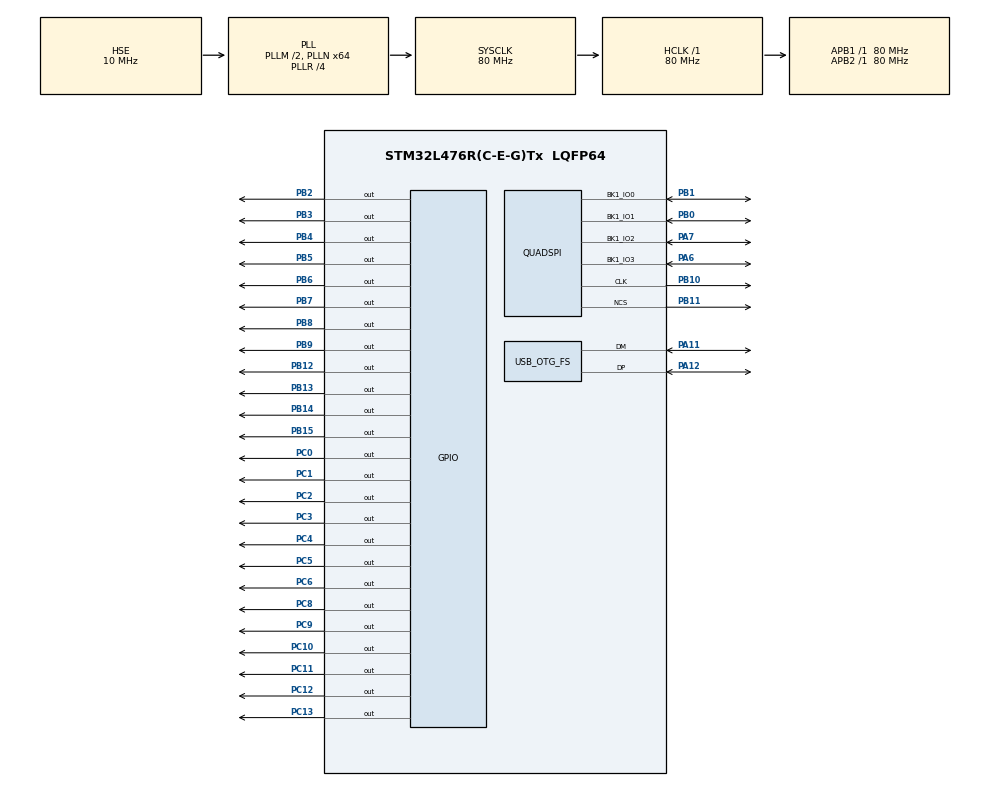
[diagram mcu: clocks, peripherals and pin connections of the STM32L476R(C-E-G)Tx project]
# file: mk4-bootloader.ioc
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CRC.InputDataFormat=CRC_INPUTDATA_FORMAT_WORDS
CRC.InputDataInversionMode=CRC_INPUTDATA_INVERSION_BYTE
CRC.OutputDataInversionMode=CRC_OUTPUTDATA_INVERSION_ENABLE
Dma.Request0=TIM1_UP
Dma.Request1=TIM4_UP
Dma.TIM1_UP.0.Direction=DMA_MEMORY_TO_PERIPH
Dma.TIM1_UP.0.Instance=DMA1_Channel6
Dma.TIM1_UP.0.MemDataAlignment=DMA_MDATAALIGN_HALFWORD
Dma.TIM1_UP.0.MemInc=DMA_MINC_ENABLE
Dma.TIM1_UP.0.Mode=DMA_CIRCULAR
Dma.TIM1_UP.0.PeriphDataAlignment=DMA_PDATAALIGN_HALFWORD
Dma.TIM1_UP.0.PeriphInc=DMA_PINC_DISABLE
Dma.TIM1_UP.0.Priority=DMA_PRIORITY_LOW
Dma.TIM4_UP.1.Direction=DMA_MEMORY_TO_PERIPH
Dma.TIM4_UP.1.Instance=DMA1_Channel7
Dma.TIM4_UP.1.MemDataAlignment=DMA_MDATAALIGN_HALFWORD
Dma.TIM4_UP.1.MemInc=DMA_MINC_ENABLE
Dma.TIM4_UP.1.Mode=DMA_CIRCULAR
Dma.TIM4_UP.1.PeriphDataAlignment=DMA_PDATAALIGN_HALFWORD
Dma.TIM4_UP.1.PeriphInc=DMA_PINC_DISABLE
Dma.TIM4_UP.1.Priority=DMA_PRIORITY_LOW
FATFS._FS_LOCK=0
FATFS._FS_READONLY=1
FATFS._MAX_SS=4096
FATFS._MIN_SS=4096
Mcu.Family=STM32L4
Mcu.Name=STM32L476R(C-E-G)Tx
Mcu.Package=LQFP64
NVIC.DMA1_Channel6_IRQn=true\:0\:0\:false\:false\:true\:false\:true
NVIC.DMA1_Channel7_IRQn=true\:0\:0\:false\:false\:true\:false\:true
NVIC.OTG_FS_IRQn=true\:0\:0\:false\:false\:true\:false\:true
NVIC.PriorityGroup=NVIC_PRIORITYGROUP_4
PA11.Mode=Device_Only
PA11.Signal=USB_OTG_FS_DM
PA12.Mode=Device_Only
PA12.Signal=USB_OTG_FS_DP
PA6.Mode=Single Bank
PA6.Signal=QUADSPI_BK1_IO3
PA7.Mode=Single Bank
PA7.Signal=QUADSPI_BK1_IO2
PB0.Mode=Single Bank
PB0.Signal=QUADSPI_BK1_IO1
PB1.Mode=Single Bank
PB1.Signal=QUADSPI_BK1_IO0
PB10.Mode=Single Bank
PB10.Signal=QUADSPI_CLK
PB11.Mode=Single Bank
PB11.Signal=QUADSPI_NCS
PB12.Signal=GPIO_Output
PB13.Signal=GPIO_Output
PB14.Signal=GPIO_Output
PB15.Signal=GPIO_Output
PB2.Signal=GPIO_Output
PB3\ (JTDO-TRACESWO).Signal=GPIO_Output
PB4\ (NJTRST).Signal=GPIO_Output
PB5.Signal=GPIO_Output
PB6.Signal=GPIO_Output
PB7.Signal=GPIO_Output
PB8.Signal=GPIO_Output
PB9.Signal=GPIO_Output
PC0.Signal=GPIO_Output
PC1.Signal=GPIO_Output
PC10.Signal=GPIO_Output
PC11.Signal=GPIO_Output
PC12.Signal=GPIO_Output
PC13.Signal=GPIO_Output
PC14-OSC32_IN\ (PC14).Mode=LSE-External-Oscillator
PC14-OSC32_IN\ (PC14).Signal=RCC_OSC32_IN
PC15-OSC32_OUT\ (PC15).Mode=LSE-External-Oscillator
PC15-OSC32_OUT\ (PC15).Signal=RCC_OSC32_OUT
PC2.Signal=GPIO_Output
PC3.Signal=GPIO_Output
PC4.Signal=GPIO_Output
PC5.Signal=GPIO_Output
PC6.Signal=GPIO_Output
PC8.Signal=GPIO_Output
PC9.Signal=GPIO_Output
PH0-OSC_IN\ (PH0).Mode=HSE-External-Oscillator
PH0-OSC_IN\ (PH0).Signal=RCC_OSC_IN
PH1-OSC_OUT\ (PH1).Mode=HSE-External-Oscillator
PH1-OSC_OUT\ (PH1).Signal=RCC_OSC_OUT
ProjectManager.HeapSize=0x200
ProjectManager.StackSize=0x400
ProjectManager.TargetToolchain=STM32CubeIDE
QUADSPI.ClockPrescaler-Single\ Bank=0
QUADSPI.FlashSize-Single\ Bank=23
QUADSPI.SampleShifting-Single\ Bank=QSPI_SAMPLE_SHIFTING_HALFCYCLE
RCC.ADCFreq_Value=20000000
RCC.AHBFreq_Value=80000000
RCC.APB1Freq_Value=80000000
RCC.APB1TimFreq_Value=80000000
RCC.APB2Freq_Value=80000000
RCC.APB2TimFreq_Value=80000000
RCC.CK48CLockSelection=RCC_USBCLKSOURCE_MSI
RCC.CortexFreq_Value=80000000
RCC.HCLKFreq_Value=80000000
RCC.HSE_VALUE=10000000
RCC.HSI_VALUE=16000000
RCC.MSIClockRange=RCC_MSIRANGE_11
RCC.MSI_VALUE=48000000
RCC.PLLM=2
RCC.PLLN=64
RCC.PLLR=RCC_PLLR_DIV4
RCC.PLLSourceVirtual=RCC_PLLSOURCE_HSE
RCC.SYSCLKFreq_VALUE=80000000
RCC.SYSCLKSource=RCC_SYSCLKSOURCE_PLLCLK
RCC.USBFreq_Value=48000000
RCC.VCOOutputFreq_Value=320000000
TIM1.Period=256
TIM4.Period=256
USB_DEVICE.CLASS_NAME_FS=MSC
USB_DEVICE.MSC_MEDIA_PACKET=4096
USB_DEVICE.VirtualMode=Msc
USB_DEVICE.VirtualModeFS=Msc_FS
USB_OTG_FS.VirtualMode=Device_Only
VP_CRC_VS_CRC.Mode=CRC_Activate
VP_FATFS_VS_Generic.Mode=User_defined
VP_TIM1_VS_ClockSourceINT.Mode=Internal
VP_TIM4_VS_ClockSourceINT.Mode=Internal
VP_USB_DEVICE_VS_USB_DEVICE_MSC_FS.Mode=MSC_FS
board=custom

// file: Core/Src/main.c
/* USER CODE BEGIN Header */
/**
  ******************************************************************************
  * @file           : main.c
  * @brief          : Main program body
  ******************************************************************************
  * @attention
  *
  * <h2><center>&copy; Copyright (c) 2021 STMicroelectronics.
  * All rights reserved.</center></h2>
  *
  * This software component is licensed by ST under BSD 3-Clause license,
  * the "License"; You may not use this file except in compliance with the
  * License. You may obtain a copy of the License at:
  *                        opensource.org/licenses/BSD-3-Clause
  *
  ******************************************************************************
  */
/* USER CODE END Header */

#include "main.h"
#include "fatfs.h"
#include "usb_device.h"

/* USER CODE BEGIN Includes */
#include "qspi_drv.h"
/* USER CODE END Includes */

CRC_HandleTypeDef hcrc;

QSPI_HandleTypeDef hqspi;

TIM_HandleTypeDef htim1;
TIM_HandleTypeDef htim4;
DMA_HandleTypeDef hdma_tim1_up;
DMA_HandleTypeDef hdma_tim4_up;

void SystemClock_Config(void);
static void MX_GPIO_Init(void);
static void MX_DMA_Init(void);
static void MX_CRC_Init(void);
static void MX_QUADSPI_Init(void);
static void MX_TIM1_Init(void);
static void MX_TIM4_Init(void);

/* USER CODE BEGIN 0 */

#define byteswap32(x) \
   ( ((x & 0xff000000) >> 24) | ((x & 0x00ff0000) >> 8) \
   | ((x & 0x0000ff00) <<  8) | ((x & 0x000000ff) << 24))

struct {
  uint8_t low;
  uint8_t high;
} buffer_c[80] = {0};

uint16_t buffer_b[80] = {0};
uint8_t animationPeriod = 2;

char animationFrame=99;
#define startAnimation() animationFrame=0
#define stopAnimation() animationFrame=99

// This method of passing variables from the linker script assumes everything is an address.
// boot size is obviously not an address, but this still works, so whatever.
extern uint32_t _boot_size[];
extern uint32_t _app_start[];
extern uint32_t _app_size[];

#define BOOT_SIZE (int)_boot_size
#define APP_SIZE (int)_app_size

void setDisplayPWM(uint32_t bright){
  HAL_DMA_Abort(&hdma_tim1_up);
  HAL_DMA_Abort(&hdma_tim4_up);
  HAL_DMA_Start(&hdma_tim1_up, (uint32_t)buffer_b, (uint32_t)&GPIOB->ODR, bright);
  HAL_DMA_Start(&hdma_tim4_up, (uint32_t)buffer_c, (uint32_t)&GPIOC->ODR, bright);
}

volatile uint8_t ejected_state = 0;

void hang_error(uint16_t errno){
  MX_USB_DEVICE_Init();

  stopAnimation();
  setDisplayPWM(5);

  buffer_b[0] = bCat0 | 0b0111110000; //b
  buffer_b[1] = bCat1 | errno;

  buffer_b[4] = bCat4 | 0b0111100100; //E
  buffer_c[0].low=0b01010000; //r
  buffer_c[1].low=0b01010000; //r
  buffer_c[2].low=0b01011100; //o
  buffer_c[3].low=0b01010000; //r

  HAL_FLASH_Lock();
  while(1){
    if (ejected_state>1) NVIC_SystemReset();
  }
}

// Get the CRC of the firmware file on FATFS
// If the CRC is wrong, immediately throw an error.
// The firmware file is padded to a fixed length, we don't need to worry about lengths not divisible by 4.
uint32_t f_crc(FIL* fp)
{
#define READ_BLOCK_SIZE (4096*2)
  unsigned int rc;
  char buf[READ_BLOCK_SIZE];
  uint32_t result;

  if ((fp)->fptr !=0) // pointless but just in case
    f_rewind(fp);

  if ((fp)->obj.objsize != APP_SIZE)
    hang_error(ERR_FS_IMG_CRC_INVALID);

  hcrc.State = HAL_CRC_STATE_BUSY;
  __HAL_CRC_DR_RESET(&hcrc);

  while ((fp)->fptr < APP_SIZE -READ_BLOCK_SIZE && !fp->err) {
    f_read(fp, &buf, READ_BLOCK_SIZE, &rc);
    for (int j=0; j<READ_BLOCK_SIZE; j+=4)
      hcrc.Instance->DR = buf[j+3] | (buf[j+2]<<8) | (buf[j+1]<<16) | (buf[j]<<24);
  }
  f_read(fp, &buf, READ_BLOCK_SIZE-4, &rc);
  for (int j=0; j<READ_BLOCK_SIZE-4; j+=4)
    hcrc.Instance->DR = buf[j+3] | (buf[j+2]<<8) | (buf[j+1]<<16) | (buf[j]<<24);

  result = ~(hcrc.Instance->DR);
  hcrc.State = HAL_CRC_STATE_READY;

  f_read(fp, &buf, 4, &rc);
  if (fp->err || result != (buf[3] | (buf[2]<<8) | (buf[1]<<16) | (buf[0]<<24)) )
    hang_error(ERR_FS_IMG_CRC_INVALID);

  return result;
#undef READ_BLOCK_SIZE
}

// Get CRC of loaded image
uint32_t app_crc()
{
  uint32_t * buf = _app_start;
  hcrc.State = HAL_CRC_STATE_BUSY;
  __HAL_CRC_DR_RESET(&hcrc);

  int j;
  uint32_t t;
  for (j=0; j<(APP_SIZE/4)-1; j++) {
    t = byteswap32(buf[j]);
    hcrc.Instance->DR = t;
  }

  uint32_t result = ~(hcrc.Instance->DR);
  hcrc.State = HAL_CRC_STATE_READY;
  return result;
}

void __attribute__((naked,noreturn)) launch_app(){
  HAL_RCC_DeInit();
  HAL_DeInit();

  SysTick->CTRL = 0;
  SysTick->LOAD = 0;
  SysTick->VAL  = 0;
  SCB->VTOR = _app_start[0];

  __DSB();
  __ISB();

  // 1st entry in the vector table is stack pointer
  // 2nd entry in the vector table is the application entry point

  __set_MSP(_app_start[0]);
  ((void (*)(void)) _app_start[1])();
  __builtin_unreachable();
}

void progressBar(uint32_t addr){
#define CHUNK ( APP_SIZE / (9*16))
  static uint32_t threshold = ((uint32_t)_app_start);
  static char progress = 0;
  if (addr>threshold) {
    switch ((++progress) & 0xF0){
      case 0x00:  buffer_b[0 + 5*(progress & 0x0F)] = bCat0 | 0b0100000000; break;
      case 0x10:  buffer_b[1 + 5*(progress & 0x0F)] = bCat1 | 0b0100000000; break;
      case 0x20:  buffer_b[2 + 5*(progress & 0x0F)] = bCat2 | 0b0100000000; break;
      case 0x30:  buffer_b[3 + 5*(progress & 0x0F)] = bCat3 | 0b0100000000; break;
      case 0x40:  buffer_b[4 + 5*(progress & 0x0F)] = bCat4 | 0b0100000000; break;
      case 0x50:  buffer_c[0 + 5*(progress & 0x0F)].low =     0b01000000  ; break;
      case 0x60:  buffer_c[1 + 5*(progress & 0x0F)].low =     0b01000000  ; break;
      case 0x70:  buffer_c[2 + 5*(progress & 0x0F)].low =     0b01000000  ; break;
      case 0x80:  buffer_c[3 + 5*(progress & 0x0F)].low =     0b01000000  ; break;
    }
    threshold += CHUNK;
  }
#undef CHUNK
}

void doAnimation(){
  switch (animationFrame++){
    case 0:  buffer_b[0] = bCat0 | 0b0000110000; buffer_b[1] = bCat1 | 0b0000000000; break;
    case 1:  buffer_b[0] = bCat0 | 0b0001100000; buffer_b[1] = bCat1 | 0b0000000000; break;
    case 2:  buffer_b[0] = bCat0 | 0b0011000000; buffer_b[1] = bCat1 | 0b0000000000; break;
    case 3:  buffer_b[0] = bCat0 | 0b0010000100; buffer_b[1] = bCat1 | 0b0000000000; break;
    case 4:  buffer_b[0] = bCat0 | 0b0000001100; buffer_b[1] = bCat1 | 0b0000000000; break;
    case 5:  buffer_b[0] = bCat0 | 0b0000001000; buffer_b[1] = bCat1 | 0b0001000000; break;
    case 6:  buffer_b[0] = bCat0 | 0b0000000000; buffer_b[1] = bCat1 | 0b0001100000; break;
    case 7:  buffer_b[0] = bCat0 | 0b0000000000; buffer_b[1] = bCat1 | 0b0000110000; break;
    case 8:  buffer_b[0] = bCat0 | 0b0000000000; buffer_b[1] = bCat1 | 0b0000011000; break;
    case 9:  buffer_b[0] = bCat0 | 0b0000000000; buffer_b[1] = bCat1 | 0b0000001100; break;
    case 10: buffer_b[0] = bCat0 | 0b0000000000; buffer_b[1] = bCat1 | 0b0010000100; break;
    case 11: buffer_b[0] = bCat0 | 0b0000010000; buffer_b[1] = bCat1 | 0b0010000000; animationFrame=0; break;
    case 99: animationFrame=99; // disable animation
  }
}

void flash_erase(){
  __HAL_FLASH_CLEAR_FLAG(FLASH_FLAG_ALL_ERRORS);

  FLASH_EraseInitTypeDef EraseInitStruct;
  uint32_t PAGEError = 0;

  // Bank size / flash size are not constants, they're read from the chip
  // on STM32L476RCT6, flash is 256K and bank size is 128K
  // on STM32L476RGT6, flash is 1MB and bank size is 512K
#define FLASH_PAGES_PER_BANK (FLASH_BANK_SIZE / FLASH_PAGE_SIZE)
#define APP_START_PAGE (((int)_app_start - FLASH_BASE) / FLASH_PAGE_SIZE )

  // Erase from app start up to end of bank 1
  EraseInitStruct.TypeErase   = FLASH_TYPEERASE_PAGES;
  EraseInitStruct.Banks       = FLASH_BANK_1;
  EraseInitStruct.Page        = APP_START_PAGE;

  if (FLASH_BANK_SIZE > BOOT_SIZE + APP_SIZE)
    EraseInitStruct.NbPages   = (BOOT_SIZE + APP_SIZE)/FLASH_PAGE_SIZE - APP_START_PAGE;
  else
    EraseInitStruct.NbPages   = FLASH_PAGES_PER_BANK - APP_START_PAGE;

  if (HAL_FLASHEx_Erase(&EraseInitStruct, &PAGEError) != HAL_OK)
    hang_error(ERR_ERASE_FAILED);

  if (FLASH_BANK_SIZE > BOOT_SIZE + APP_SIZE) return;

  animationPeriod = 50;

  // Erase bank 2
  EraseInitStruct.TypeErase   = FLASH_TYPEERASE_PAGES;
  EraseInitStruct.Banks       = FLASH_BANK_2;
  EraseInitStruct.Page        = 0;
  EraseInitStruct.NbPages     = (BOOT_SIZE + APP_SIZE - FLASH_BANK_SIZE)/FLASH_PAGE_SIZE;

  if (HAL_FLASHEx_Erase(&EraseInitStruct, &PAGEError) != HAL_OK)
    hang_error(ERR_ERASE_FAILED);

}

void flash_write(FIL* fp){
  uint32_t addr = (uint32_t)_app_start;

  unsigned int rc;
  char buf[8];

  if ((fp)->fptr !=0)
    f_rewind(fp);

  while (addr < FLASH_BASE + BOOT_SIZE + APP_SIZE){
    f_read(fp, &buf, 8, &rc);
    uint32_t low = (buf[3] << 24) | (buf[2] << 16) | (buf[1] << 8) | (buf[0]);
    uint32_t high= (buf[7] << 24) | (buf[6] << 16) | (buf[5] << 8) | (buf[4]);
    uint64_t data = ((uint64_t)high << 32) | low;

    if (HAL_FLASH_Program(FLASH_TYPEPROGRAM_DOUBLEWORD, addr, data ) == HAL_OK) {
      if (*(uint64_t*)addr != data) hang_error(ERR_WRITE_INVALID);
      addr += 8;
    } else hang_error(ERR_WRITE_FAILED);

    progressBar(addr);
  }

}

/* USER CODE END 0 */

int main(void)
{

  /* MCU Configuration--------------------------------------------------------*/

  /* Reset of all peripherals, Initializes the Flash interface and the Systick. */
  HAL_Init();

  /* Configure the system clock */
  SystemClock_Config();

  /* Initialize all configured peripherals */
  MX_GPIO_Init();
  MX_DMA_Init();
  MX_CRC_Init();
  MX_QUADSPI_Init();
  MX_TIM1_Init();
  MX_TIM4_Init();
  MX_FATFS_Init();
  //MX_USB_DEVICE_Init();
  /* USER CODE BEGIN 2 */

  buffer_c[0].high=0b11001110;
  buffer_c[1].high=0b11001101;
  buffer_c[2].high=0b11001011;
  buffer_c[3].high=0b11000111;
  buffer_c[4].high=0b11001111;

//  buffer_c[0].low=0b01011100; //o
//  buffer_c[1].low=0b01011100; //o
//  buffer_c[2].low=0b01111000; //t
//  buffer_c[3].low=0;
//  buffer_c[4].low=0;
//
//  buffer_b[0] = 0;//bCat0 | bSegDecode1;
//  buffer_b[1] = 0;//bCat1 | bSegDecode2;
//  buffer_b[2] = 0;//bCat2 | bSegDecode3;
//  buffer_b[3] = 0;//bCat3 | bSegDecode4;
//  buffer_b[4] = bCat4 | 0b0111110000; //b

  if (HAL_DMA_Start(&hdma_tim1_up, (uint32_t)buffer_c, (uint32_t)&GPIOC->ODR, 5) != HAL_OK)
    Error_Handler();

  if (HAL_DMA_Start(&hdma_tim4_up, (uint32_t)buffer_b, (uint32_t)&GPIOB->ODR, 5) != HAL_OK)
    Error_Handler();

  __HAL_TIM_ENABLE_DMA(&htim1, TIM_DMA_UPDATE);
  __HAL_TIM_ENABLE(&htim1);

  __HAL_TIM_ENABLE_DMA(&htim4, TIM_DMA_UPDATE);
  __HAL_TIM_ENABLE(&htim4);

  _Bool new_fw_present;
  uint32_t new_fw_crc =0;

  // Calculate CRC of loaded image
  uint32_t loaded_fw_crc = app_crc();

  // Look for new firmware file and calculate its crc
  FIL file;

  if (f_open(&file, "/FWT.BIN", FA_READ) != FR_OK)
    new_fw_present = 0;
  else {
    new_fw_present = 1;
    new_fw_crc = f_crc(&file);
  }

// debug force reload
// new_fw_crc=0;

  // Hinge TX connection shorted to ground - force bootloader to hang
  if ((GPIOA->IDR & (1<<2))==0) {
    hang_error(ERR_USER);
  }

  if (loaded_fw_crc == byteswap32(*(uint32_t*)(FLASH_BASE + BOOT_SIZE + APP_SIZE -4)) ) { // loaded firmware valid

    if (!new_fw_present) launch_app();

    if (loaded_fw_crc == new_fw_crc) launch_app();

  } else { // loaded firmware invalid

    if (!new_fw_present) hang_error(ERR_INVALID_NO_FW);

  }

  startAnimation();

  HAL_FLASH_Unlock();
  flash_erase();

  stopAnimation();
  buffer_b[0] = 0;
  buffer_b[1] = 0;
  // Set up display for fading individual segments
  for (uint8_t i=0;i<80;i+=5) {
    buffer_c[0 + i].high=0b11001110;
    buffer_c[1 + i].high=0b11001101;
    buffer_c[2 + i].high=0b11001011;
    buffer_c[3 + i].high=0b11000111;
    buffer_c[4 + i].high=0b11001111;
  }
  setDisplayPWM(80);

  flash_write(&file);
  HAL_FLASH_Lock();

  //launch_app();
  NVIC_SystemReset();

  /* USER CODE END 2 */

  /* Infinite loop */
  while (1)
  {

  }
}

void SystemClock_Config(void)
{
  RCC_OscInitTypeDef RCC_OscInitStruct = {0};
  RCC_ClkInitTypeDef RCC_ClkInitStruct = {0};
  RCC_PeriphCLKInitTypeDef PeriphClkInit = {0};

  /** Configure LSE Drive Capability
  */
  HAL_PWR_EnableBkUpAccess();
  __HAL_RCC_LSEDRIVE_CONFIG(RCC_LSEDRIVE_LOW);
  /** Initializes the CPU, AHB and APB busses clocks
  */
  RCC_OscInitStruct.OscillatorType = RCC_OSCILLATORTYPE_HSE|RCC_OSCILLATORTYPE_LSE
                              |RCC_OSCILLATORTYPE_MSI;
  RCC_OscInitStruct.HSEState = RCC_HSE_ON;
  RCC_OscInitStruct.LSEState = RCC_LSE_ON;
  RCC_OscInitStruct.MSIState = RCC_MSI_ON;
  RCC_OscInitStruct.MSICalibrationValue = 0;
  RCC_OscInitStruct.MSIClockRange = RCC_MSIRANGE_11;
  RCC_OscInitStruct.PLL.PLLState = RCC_PLL_ON;
  RCC_OscInitStruct.PLL.PLLSource = RCC_PLLSOURCE_HSE;
  RCC_OscInitStruct.PLL.PLLM = 2;
  RCC_OscInitStruct.PLL.PLLN = 64;
  RCC_OscInitStruct.PLL.PLLP = RCC_PLLP_DIV7;
  RCC_OscInitStruct.PLL.PLLQ = RCC_PLLQ_DIV2;
  RCC_OscInitStruct.PLL.PLLR = RCC_PLLR_DIV4;
  if (HAL_RCC_OscConfig(&RCC_OscInitStruct) != HAL_OK)
  {
    Error_Handler();
  }
  /** Initializes the CPU, AHB and APB busses clocks
  */
  RCC_ClkInitStruct.ClockType = RCC_CLOCKTYPE_HCLK|RCC_CLOCKTYPE_SYSCLK
                              |RCC_CLOCKTYPE_PCLK1|RCC_CLOCKTYPE_PCLK2;
  RCC_ClkInitStruct.SYSCLKSource = RCC_SYSCLKSOURCE_PLLCLK;
  RCC_ClkInitStruct.AHBCLKDivider = RCC_SYSCLK_DIV1;
  RCC_ClkInitStruct.APB1CLKDivider = RCC_HCLK_DIV1;
  RCC_ClkInitStruct.APB2CLKDivider = RCC_HCLK_DIV1;

  if (HAL_RCC_ClockConfig(&RCC_ClkInitStruct, FLASH_LATENCY_4) != HAL_OK)
  {
    Error_Handler();
  }
  PeriphClkInit.PeriphClockSelection = RCC_PERIPHCLK_USB;
  PeriphClkInit.UsbClockSelection = RCC_USBCLKSOURCE_MSI;
  if (HAL_RCCEx_PeriphCLKConfig(&PeriphClkInit) != HAL_OK)
  {
    Error_Handler();
  }
  /** Configure the main internal regulator output voltage
  */
  if (HAL_PWREx_ControlVoltageScaling(PWR_REGULATOR_VOLTAGE_SCALE1) != HAL_OK)
  {
    Error_Handler();
  }
  /** Enable MSI Auto calibration
  */
  HAL_RCCEx_EnableMSIPLLMode();
}

static void MX_CRC_Init(void)
{

  hcrc.Instance = CRC;
  hcrc.Init.DefaultPolynomialUse = DEFAULT_POLYNOMIAL_ENABLE;
  hcrc.Init.DefaultInitValueUse = DEFAULT_INIT_VALUE_ENABLE;
  hcrc.Init.InputDataInversionMode = CRC_INPUTDATA_INVERSION_BYTE;
  hcrc.Init.OutputDataInversionMode = CRC_OUTPUTDATA_INVERSION_ENABLE;
  hcrc.InputDataFormat = CRC_INPUTDATA_FORMAT_WORDS;
  if (HAL_CRC_Init(&hcrc) != HAL_OK)
  {
    Error_Handler();
  }

}

static void MX_QUADSPI_Init(void)
{

  /* QUADSPI parameter configuration*/
  hqspi.Instance = QUADSPI;
  hqspi.Init.ClockPrescaler = 0;
  hqspi.Init.FifoThreshold = 1;
  hqspi.Init.SampleShifting = QSPI_SAMPLE_SHIFTING_HALFCYCLE;
  hqspi.Init.FlashSize = 23;
  hqspi.Init.ChipSelectHighTime = QSPI_CS_HIGH_TIME_1_CYCLE;
  hqspi.Init.ClockMode = QSPI_CLOCK_MODE_0;
  if (HAL_QSPI_Init(&hqspi) != HAL_OK)
  {
    Error_Handler();
  }

}

static void MX_TIM1_Init(void)
{

  TIM_ClockConfigTypeDef sClockSourceConfig = {0};
  TIM_MasterConfigTypeDef sMasterConfig = {0};

  htim1.Instance = TIM1;
  htim1.Init.Prescaler = 0;
  htim1.Init.CounterMode = TIM_COUNTERMODE_UP;
  htim1.Init.Period = 256;
  htim1.Init.ClockDivision = TIM_CLOCKDIVISION_DIV1;
  htim1.Init.RepetitionCounter = 0;
  htim1.Init.AutoReloadPreload = TIM_AUTORELOAD_PRELOAD_DISABLE;
  if (HAL_TIM_Base_Init(&htim1) != HAL_OK)
  {
    Error_Handler();
  }
  sClockSourceConfig.ClockSource = TIM_CLOCKSOURCE_INTERNAL;
  if (HAL_TIM_ConfigClockSource(&htim1, &sClockSourceConfig) != HAL_OK)
  {
    Error_Handler();
  }
  sMasterConfig.MasterOutputTrigger = TIM_TRGO_RESET;
  sMasterConfig.MasterOutputTrigger2 = TIM_TRGO2_RESET;
  sMasterConfig.MasterSlaveMode = TIM_MASTERSLAVEMODE_DISABLE;
  if (HAL_TIMEx_MasterConfigSynchronization(&htim1, &sMasterConfig) != HAL_OK)
  {
    Error_Handler();
  }

}

static void MX_TIM4_Init(void)
{

  TIM_ClockConfigTypeDef sClockSourceConfig = {0};
  TIM_MasterConfigTypeDef sMasterConfig = {0};

  htim4.Instance = TIM4;
  htim4.Init.Prescaler = 0;
  htim4.Init.CounterMode = TIM_COUNTERMODE_UP;
  htim4.Init.Period = 256;
  htim4.Init.ClockDivision = TIM_CLOCKDIVISION_DIV1;
  htim4.Init.AutoReloadPreload = TIM_AUTORELOAD_PRELOAD_DISABLE;
  if (HAL_TIM_Base_Init(&htim4) != HAL_OK)
  {
    Error_Handler();
  }
  sClockSourceConfig.ClockSource = TIM_CLOCKSOURCE_INTERNAL;
  if (HAL_TIM_ConfigClockSource(&htim4, &sClockSourceConfig) != HAL_OK)
  {
    Error_Handler();
  }
  sMasterConfig.MasterOutputTrigger = TIM_TRGO_RESET;
  sMasterConfig.MasterSlaveMode = TIM_MASTERSLAVEMODE_DISABLE;
  if (HAL_TIMEx_MasterConfigSynchronization(&htim4, &sMasterConfig) != HAL_OK)
  {
    Error_Handler();
  }

}

static void MX_DMA_Init(void)
{

  /* DMA controller clock enable */
  __HAL_RCC_DMA1_CLK_ENABLE();

  /* DMA interrupt init */
  /* DMA1_Channel6_IRQn interrupt configuration */
  HAL_NVIC_SetPriority(DMA1_Channel6_IRQn, 0, 0);
  HAL_NVIC_EnableIRQ(DMA1_Channel6_IRQn);
  /* DMA1_Channel7_IRQn interrupt configuration */
  HAL_NVIC_SetPriority(DMA1_Channel7_IRQn, 0, 0);
  HAL_NVIC_EnableIRQ(DMA1_Channel7_IRQn);

}

static void MX_GPIO_Init(void)
{
  GPIO_InitTypeDef GPIO_InitStruct = {0};

  /* GPIO Ports Clock Enable */
  __HAL_RCC_GPIOC_CLK_ENABLE();
  __HAL_RCC_GPIOH_CLK_ENABLE();
  __HAL_RCC_GPIOA_CLK_ENABLE();
  __HAL_RCC_GPIOB_CLK_ENABLE();

  /*Configure GPIO pin Output Level */
  HAL_GPIO_WritePin(GPIOA, GPIO_PIN_0|GPIO_PIN_1, GPIO_PIN_SET);

  /*Configure GPIO pin : PA0 PA1 */
  GPIO_InitStruct.Pin = GPIO_PIN_0|GPIO_PIN_1;
  GPIO_InitStruct.Mode = GPIO_MODE_OUTPUT_PP;
  GPIO_InitStruct.Pull = GPIO_NOPULL;
  GPIO_InitStruct.Speed = GPIO_SPEED_FREQ_LOW;
  HAL_GPIO_Init(GPIOA, &GPIO_InitStruct);

  /**USART2 GPIO Configuration
  PA2     ------> USART2_TX
  PA3     ------> USART2_RX
  */
  GPIO_InitStruct.Pin = GPIO_PIN_2;
  GPIO_InitStruct.Mode = GPIO_MODE_INPUT;
  GPIO_InitStruct.Pull = GPIO_PULLUP;
  HAL_GPIO_Init(GPIOA, &GPIO_InitStruct);

  /*Configure GPIO pin Output Level */
  HAL_GPIO_WritePin(GPIOC, GPIO_PIN_13|GPIO_PIN_0|GPIO_PIN_1|GPIO_PIN_2
                          |GPIO_PIN_3|GPIO_PIN_4|GPIO_PIN_5|GPIO_PIN_6
                          |GPIO_PIN_8|GPIO_PIN_9|GPIO_PIN_10|GPIO_PIN_11
                          |GPIO_PIN_12, GPIO_PIN_RESET);

  /*Configure GPIO pin Output Level */
  HAL_GPIO_WritePin(GPIOB, GPIO_PIN_2|GPIO_PIN_12|GPIO_PIN_13|GPIO_PIN_14
                          |GPIO_PIN_15|GPIO_PIN_3|GPIO_PIN_4|GPIO_PIN_5
                          |GPIO_PIN_6|GPIO_PIN_7|GPIO_PIN_8|GPIO_PIN_9, GPIO_PIN_RESET);

  /*Configure GPIO pins : PC13 PC0 PC1 PC2
                           PC3 PC4 PC5 PC6
                           PC8 PC9 PC10 PC11
                           PC12 */
  GPIO_InitStruct.Pin = GPIO_PIN_13|GPIO_PIN_0|GPIO_PIN_1|GPIO_PIN_2
                          |GPIO_PIN_3|GPIO_PIN_4|GPIO_PIN_5|GPIO_PIN_6
                          |GPIO_PIN_8|GPIO_PIN_9|GPIO_PIN_10|GPIO_PIN_11
                          |GPIO_PIN_12;
  GPIO_InitStruct.Mode = GPIO_MODE_OUTPUT_PP;
  GPIO_InitStruct.Pull = GPIO_NOPULL;
  GPIO_InitStruct.Speed = GPIO_SPEED_FREQ_LOW;
  HAL_GPIO_Init(GPIOC, &GPIO_InitStruct);

  /*Configure GPIO pins : PB2 PB12 PB13 PB14
                           PB15 PB3 PB4 PB5
                           PB6 PB7 PB8 PB9 */
  GPIO_InitStruct.Pin = GPIO_PIN_2|GPIO_PIN_12|GPIO_PIN_13|GPIO_PIN_14
                          |GPIO_PIN_15|GPIO_PIN_3|GPIO_PIN_4|GPIO_PIN_5
                          |GPIO_PIN_6|GPIO_PIN_7|GPIO_PIN_8|GPIO_PIN_9;
  GPIO_InitStruct.Mode = GPIO_MODE_OUTPUT_PP;
  GPIO_InitStruct.Pull = GPIO_NOPULL;
  GPIO_InitStruct.Speed = GPIO_SPEED_FREQ_LOW;
  HAL_GPIO_Init(GPIOB, &GPIO_InitStruct);

}

void Error_Handler(void)
{
  /* USER CODE BEGIN Error_Handler_Debug */
  /* User can add his own implementation to report the HAL error return state */
  hang_error(ERR_UNKNOWN);
  /* USER CODE END Error_Handler_Debug */
}

/************************ (C) COPYRIGHT STMicroelectronics *****END OF FILE****/
